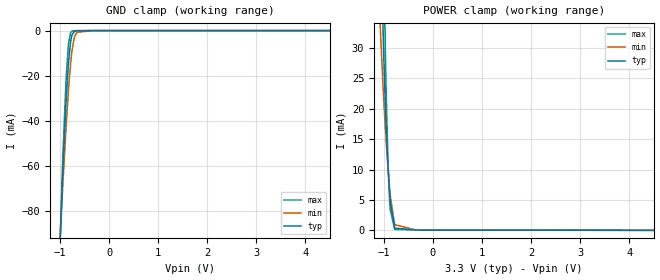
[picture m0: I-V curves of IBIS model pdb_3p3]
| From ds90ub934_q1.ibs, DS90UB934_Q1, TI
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|   pdb_3p3 Model
[Model]   pdb_3p3
Model_type   Input
Vinl = 0.8
Vinh = 2.0
|   typ   min   max
|   (nom PVT)   (fast PVT)   (slow PVT)
C_comp   3.681e-13   2.804e-13   4.593e-13
| Where nom  PVT is Nominal Process, 3.3V, 27C
|   Fast PVT is Strong Process,  3.6V, -40C
|   Slow PVT is Weak Process,   3V, 125C
[Voltage Range]   3.3   3   3.6
|Junction Temperature
[Temperature Range]   27   125   -40
[Power Clamp Reference]   3.3   3   3.6
[GND Clamp Reference]   0   0   0
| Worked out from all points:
|   GND clamp passes 1 mA (typ) near -0.73 V on its own axis
|   POWER clamp passes 1 mA (typ) near -0.79 V on its own axis
[GND Clamp]
|   Voltage   I(typ)   I(min)   I(max)
-3.3V     -1.797A    -1.612A    -1.945A
-1.064V   -133.6mA   -125.7mA   -138.3mA
-1.006V   -97.21mA   -96.37mA   -97.14mA
-943.8mV  -61.67mA   -68.3mA    -56.21mA
-879mV    -31.66mA   -43.11mA   -21.94mA
-828mV    -14.09mA   -26.09mA   -5.559mA
-785.4mV  -4.87mA    -14.55mA   -910.5uA
-758.4mV  -1.986mA   -8.99mA    -260uA
-706.2mV  -276.2uA   -2.713mA   -41.23uA
-660mV    -56.83uA   -778.2uA   -23.84uA
-330mV    -10.79uA   -9.203uA   -13.02uA
6.6V      0A         0A         0A
[POWER Clamp]
|   Voltage   I(typ)   I(min)   I(max)
-3.3V     1.763A     1.504A     1.972A
-1.073V   55.6mA     33.35mA    89.82mA
-1.016V   33.03mA    23.62mA    53.7mA
-1.003V   28.93mA    21.62mA    46.15mA
-960mV    18.29mA    15.63mA    25.27mA
-957mV    17.68mA    15.24mA    24.08mA
-916.8mV  10.65mA    10.4mA     11.45mA
-881.1mV  5.938mA    6.743mA    4.812mA
-870mV    4.762mA    5.756mA    3.458mA
-778.8mV  382.2uA    949.9uA    176.4uA
-330mV    72.53uA    57.25uA    93.64uA
6.6V      0A         0A         0A
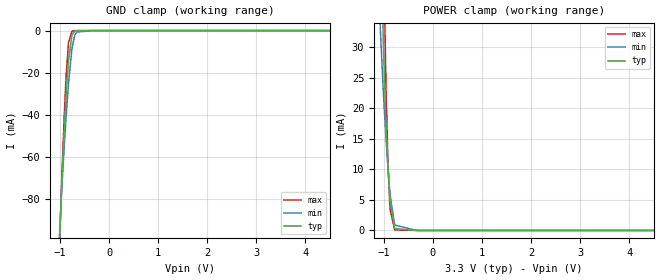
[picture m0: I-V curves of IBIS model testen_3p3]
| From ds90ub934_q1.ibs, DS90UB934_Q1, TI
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|   testen_3p3 Model
[Model]   testen_3p3
Model_type   Input
Vinl = 0.8
Vinh = 2.0
|   typ   min   max
|   (nom PVT)   (fast PVT)   (slow PVT)
C_comp   3.055e-13   2.043e-13   4.168e-13
| Where nom  PVT is Nominal Process, 3.3V, 27C
|   Fast PVT is Strong Process,  3.6V, -40C
|   Slow PVT is Weak Process,   3V, 125C
[Voltage Range]   3.3   3   3.6
|Junction Temperature
[Temperature Range]   27   125   -40
[Power Clamp Reference]   3.3   3   3.6
[GND Clamp Reference]   0   0   0
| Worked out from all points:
|   GND clamp passes 1 mA (typ) near -0.73 V on its own axis
|   POWER clamp passes 1 mA (typ) near -0.79 V on its own axis
[GND Clamp]
|   Voltage   I(typ)   I(min)   I(max)
-3.3V     -1.759A    -1.583A    -1.903A
-1.077V   -139.9mA   -129.1mA   -147.7mA
-1.046V   -120.4mA   -113.2mA   -125.7mA
-960.3mV  -69.8mA    -73.13mA   -67.15mA
-912mV    -45.67mA   -53.72mA   -38.51mA
-876mV    -30.4mA    -40.59mA   -21.01mA
-828mV    -14.16mA   -25.05mA   -5.707mA
-758.4mV  -2.04mA    -8.454mA   -275.7uA
-702.9mV  -257uA     -2.263mA   -28.48uA
-660mV    -52.91uA   -694.8uA   -11.39uA
-330mV    -1.485uA   -1.51uA    -1.725uA
6.6V      0A         0A         0A
[POWER Clamp]
|   Voltage   I(typ)   I(min)   I(max)
-3.3V     1.763A     1.504A     1.971A
-1.073V   55.52mA    33.28mA    89.72mA
-1.016V   32.94mA    23.55mA    53.59mA
-1.003V   28.85mA    21.56mA    46.04mA
-960mV    18.21mA    15.56mA    25.17mA
-957mV    17.6mA     15.17mA    23.97mA
-916.8mV  10.57mA    10.33mA    11.34mA
-881.1mV  5.858mA    6.679mA    4.711mA
-870mV    4.683mA    5.693mA    3.357mA
-778.8mV  304.8uA    888uA      77.36uA
-330mV    3.603uA    2.755uA    4.801uA
6.6V      0A         0A         0A
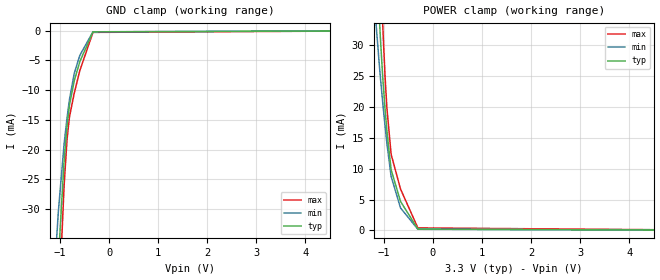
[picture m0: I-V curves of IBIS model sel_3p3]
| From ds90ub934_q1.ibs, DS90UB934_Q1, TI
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|   sel_3p3 Model
[Model]   sel_3p3
Model_type   Input
Vinl = 0.8
Vinh = 2
|   typ   min   max
|   (nom PVT)   (fast PVT)   (slow PVT)
C_comp   3.725e-13   3.725e-13   4.390e-13
| Where nom  PVT is Nominal Process, 3.3V, 27C
|   Fast PVT is Strong Process,  3.6V, -40C
|   Slow PVT is Weak Process,   3V, 125C
[Voltage Range]   3.3   3   3.6
[Temperature Range]   27   125   -40
[Power Clamp Reference]   3.3   3   3.6
[GND Clamp Reference]   0   0   0
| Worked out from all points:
|   GND clamp passes 1 mA (typ) near -0.38 V on its own axis
[GND Clamp]
|   Voltage   I(typ)   I(min)   I(max)
-3.3V     -491.8mA   -423.9mA   -559.8mA
-1.239V   -75.42mA   -59.14mA   -91.74mA
-1.131V   -55.26mA   -42.87mA   -68mA
-1.118V   -52.97mA   -41.09mA   -65.28mA
-1.035V   -38.5mA    -30.32mA   -47.74mA
-916.8mV  -21.68mA   -18.91mA   -25.82mA
-858mV    -16mA      -14.63mA   -18.24mA
-808.8mV  -12.51mA   -11.55mA   -14.49mA
-711mV    -8.408mA   -7.157mA   -10.49mA
-597mV    -5.192mA   -4.143mA   -6.684mA
-330mV    -214.7uA   -206.2uA   -301.9uA
6.6V      0A         0A         0A
[POWER Clamp]
|   Voltage   I(typ)   I(min)   I(max)
-3.3V     582.6mA    466.2mA    697.7mA
-1.155V   45.95mA    33.09mA    64.94mA
-1.089V   34.1mA     26.5mA     48.29mA
-1.072V   31.39mA    24.92mA    44.15mA
-1.023V   24.87mA    20.74mA    33.49mA
-1.014V   23.81mA    19.99mA    31.71mA
-975mV    19.64mA    16.89mA    24.89mA
-937.2mV  16.08mA    14.07mA    19.74mA
-852mV    9.838mA    8.767mA    12.34mA
-660mV    4.699mA    3.648mA    6.709mA
-306.9mV  228.3uA    198.8uA    415.9uA
6.6V      0A         0A         0A
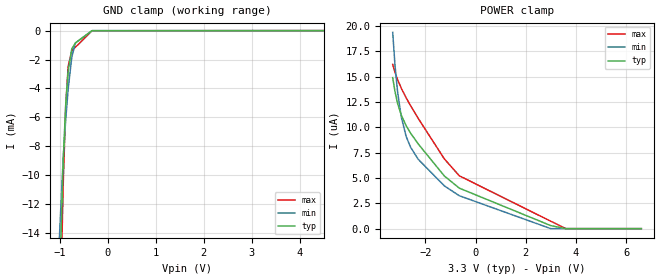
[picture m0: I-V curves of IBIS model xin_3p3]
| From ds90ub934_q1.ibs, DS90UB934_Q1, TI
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|   xin_3p3 Model
[Model]   xin_3p3
Model_type   Input
Vinl = 0.8
Vinh = 2
|   typ   min   max
|   (nom PVT)   (fast PVT)   (slow PVT)
C_comp   1.620e-13   1.261e-13   2.014e-13
| Where nom  PVT is Nominal Process, 3.3V, 27C
|   Fast PVT is Strong Process,  3.6V, -40C
|   Slow PVT is Weak Process,   3V, 125C
[Voltage Range]   3.3   3   3.6
|Junction Temperature
[Temperature Range]   27   125   -40
[Power Clamp Reference]   3.3   3   3.6
[GND Clamp Reference]   0   0   0
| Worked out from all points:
|   GND clamp passes 1 mA (typ) near -0.71 V on its own axis
[GND Clamp]
|   Voltage   I(typ)   I(min)   I(max)
-3.3V     -430mA     -361.4mA   -493.6mA
-1.134V   -36.71mA   -27.33mA   -45.03mA
-1.072V   -26.93mA   -20.21mA   -33.21mA
-1.043V   -22.67mA   -17.3mA    -27.98mA
-1.007V   -17.67mA   -14.08mA   -21.78mA
-930.6mV  -9.002mA   -8.818mA   -10.62mA
-877.8mV  -5.092mA   -6.133mA   -5.214mA
-826.8mV  -2.792mA   -4.031mA   -2.458mA
-751.2mV  -1.26mA    -1.833mA   -1.393mA
-675mV    -852.5uA   -851uA     -1.149mA
-330mV    -7.435uA   -6.971uA   -11.19uA
6.6V      0A         0A         0A
[POWER Clamp]
|   Voltage   I(typ)   I(min)   I(max)
-3.3V     14.9uA     19.36uA    16.2uA
-3.21V    13.53uA    16.15uA    15.43uA
-3.106V   12.36uA    13.49uA    14.7uA
-2.958V   11.2uA     11.01uA    13.85uA
-2.766V   10.16uA    9.105uA    12.91uA
-2.591V   9.43uA     8.045uA    12.14uA
-2.277V   8.336uA    6.822uA    10.85uA
-1.244V   5.196uA    4.223uA    6.88uA
-646.8mV  3.995uA    3.246uA    5.211uA
2.997V    297.9nA    0A         732.8nA
3.594V    0A         0A         0A
6.6V      0A         0A         0A
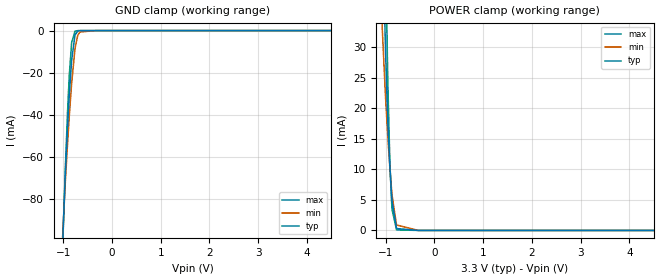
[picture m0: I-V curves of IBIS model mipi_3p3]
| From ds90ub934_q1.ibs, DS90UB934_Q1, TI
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|   mipi_3p3 Model
[Model]   mipi_3p3
Model_type   Input
Vinl = 0.8
Vinh = 2
|   typ   min   max
|   (nom PVT)   (fast PVT)   (slow PVT)
C_comp   3.055e-13   2.043e-13   4.178e-13
| Where nom  PVT is Nominal Process, 3.3V, 27C
|   Fast PVT is Strong Process,  3.6V, -40C
|   Slow PVT is Weak Process,   3V, 125C
[Voltage Range]   3.3   3   3.6
|Junction Temperature
[Temperature Range]   27   125   -40
[Power Clamp Reference]   3.3   3   3.6
[GND Clamp Reference]   0   0   0
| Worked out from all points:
|   GND clamp passes 1 mA (typ) near -0.73 V on its own axis
|   POWER clamp passes 1 mA (typ) near -0.79 V on its own axis
[GND Clamp]
|   Voltage   I(typ)   I(min)   I(max)
-3.3V     -1.759A    -1.583A    -1.903A
-1.077V   -139.9mA   -129.1mA   -147.7mA
-1.046V   -120.4mA   -113.2mA   -125.7mA
-960.3mV  -69.79mA   -73.12mA   -67.13mA
-912mV    -45.66mA   -53.71mA   -38.49mA
-876mV    -30.39mA   -40.58mA   -21mA
-828mV    -14.15mA   -25.04mA   -5.695mA
-758.4mV  -2.032mA   -8.447mA   -265.5uA
-702.9mV  -249.6uA   -2.256mA   -19.47uA
-660mV    -46.28uA   -689.1uA   -3.329uA
-330mV    -336.9nA   -350.4nA   -407.3nA
6.6V      0A         0A         0A
[POWER Clamp]
|   Voltage   I(typ)   I(min)   I(max)
-3.3V     1.763A     1.504A     1.972A
-1.073V   55.54mA    33.29mA    89.74mA
-1.016V   32.96mA    23.57mA    53.61mA
-1.003V   28.87mA    21.57mA    46.06mA
-960mV    18.22mA    15.57mA    25.18mA
-957mV    17.61mA    15.19mA    23.99mA
-916.8mV  10.59mA    10.35mA    11.36mA
-881.1mV  5.872mA    6.691mA    4.728mA
-870mV    4.697mA    5.705mA    3.373mA
-778.8mV  316.4uA    897.9uA    91.82uA
-330mV    6.563uA    5.362uA    8.631uA
6.6V      0A         0A         0A
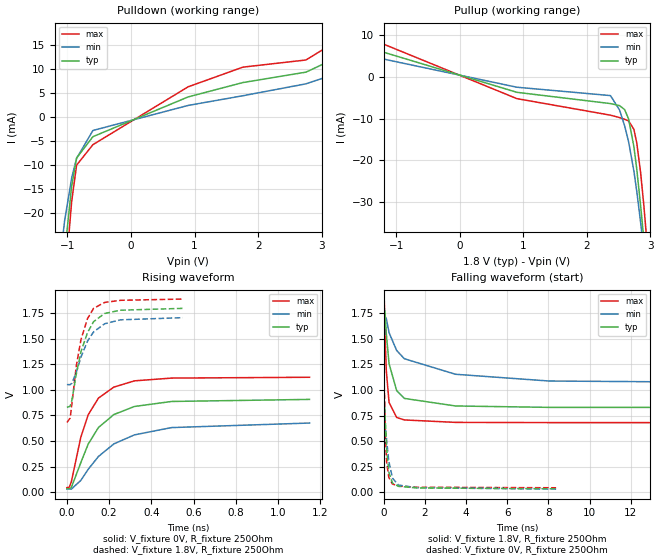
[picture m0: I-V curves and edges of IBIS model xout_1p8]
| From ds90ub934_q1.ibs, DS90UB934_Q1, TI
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|   xout_1p8 Model
[Model]   xout_1p8
Model_type   Output
Polarity   Inverting
Vmeas = 0.9
Vref = 0
Cref = 2pF
Rref = 400
|   typ   min   max
|   (nom PVT)   (fast PVT)   (slow PVT)
C_comp   3.237e-13   3.075e-13   3.282e-13
| Where nom  PVT is Nominal Process, 1.8V, 27C
|   Fast PVT is Strong Process,  1.89V, -40C
|   Slow PVT is Weak Process,   1.71V, 125C
[Voltage Range]   1.8   1.71   1.89
|Junction Temperature
[Temperature Range]   27   125   -40
[Pullup Reference]   1.8   1.71   1.89
[Pulldown Reference]   0   0   0
[Power Clamp Reference]   1.8   1.71   1.89
[GND Clamp Reference]   0   0   0
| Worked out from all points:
|   slope of the pulldown table from 0 to 0.27 V, typ, clamps not added: 169 ohm
|   slope of the pullup table from 0 to 0.27 V, typ, clamps not added: 222 ohm
|   falling waveform, V_fixture 1.8V, R_fixture 250Ohm: 20-80 % time 458ps typ, 2.41ns min, 175ps max; typ from 1.8 V to 0.828 V
|   rising waveform, V_fixture 0V, R_fixture 250Ohm: 20-80 % time 149ps typ, 218ps min, 107ps max; typ from 0.034 V to 0.906 V
|   rising waveform, V_fixture 1.8V, R_fixture 250Ohm: 20-80 % time 73.6ps typ, 83.7ps min, 62.1ps max; typ from 0.828 V to 1.8 V
|   falling waveform, V_fixture 0V, R_fixture 250Ohm: 20-80 % time 165ps typ, 265ps min, 113ps max; typ from 0.91 V to 0.034 V
[Pulldown]
|   Voltage   I(typ)   I(min)   I(max)
-1.8V     -162.8mA   -133.4mA   -187.7mA
-1.21V    -55.41mA   -41.88mA   -66.96mA
-1.146V   -44.56mA   -33.31mA   -54.29mA
-1.112V   -39.05mA   -29.13mA   -47.79mA
-1.044V   -28.43mA   -21.55mA   -35.11mA
-934.7mV  -14.46mA   -12.78mA   -17.7mA
-856.8mV  -8.583mA   -8.654mA   -10.07mA
-599.6mV  -4.133mA   -2.843mA   -5.796mA
898.4mV   4.142mA    2.37mA     6.249mA
1.761V    7.14mA     4.392mA    10.35mA
2.753V    9.305mA    6.871mA    11.84mA
3.6V      14.56mA    10.6mA     18.71mA
[Pullup]
|   Voltage   I(typ)   I(min)   I(max)
-1.8V     8.725mA    6.251mA    11.66mA
898.4mV   -3.677mA   -2.454mA   -5.198mA
2.371V    -6.387mA   -4.465mA   -9.173mA
2.514V    -6.876mA   -7.943mA   -9.755mA
2.595V    -7.838mA   -11.78mA   -10.17mA
2.657V    -10.15mA   -15.61mA   -10.56mA
2.74V     -16.77mA   -22.66mA   -12.6mA
2.785V    -22.19mA   -27.51mA   -15.86mA
2.846V    -31mA      -35.03mA   -23.07mA
2.897V    -39.16mA   -41.89mA   -31.01mA
2.957V    -49.38mA   -50.47mA   -41.83mA
3.6V      -168.8mA   -151.8mA   -176.6mA
[Ramp]
R_load = 250
|   typ   min   max
dV/dt_r   0.526075/1.51331e-10   0.391085/2.25282e-10   0.649945/1.08163e-10
dV/dt_f   0.582641/4.56977e-10   0.395262/2.42675e-09   0.725076/1.74409e-10
[Falling Waveform]
V_fixture = 1.8V
V_fixture_min = 1.71V
V_fixture_max = 1.89V
R_fixture = 250Ohm
|   Time   V(typ)   V(min)   V(max)
0s        1.8V       1.71V      1.89V
35.45ps   1.806V     1.714V     1.871V
81.15ps   1.739V     1.713V     1.484V
133.9ps   1.548V     1.699V     1.188V
266.9ps   1.257V     1.561V     878.3mV
636.2ps   994mV      1.387V     731.3mV
1.009ns   917.8mV    1.306V     707.2mV
3.494ns   843.8mV    1.154V     683.2mV
8.033ns   830.2mV    1.088V     681.1mV
34.51ns   828.3mV    1.051V     680.8mV
[Rising Waveform]
V_fixture = 0V
V_fixture_min = 0V
V_fixture_max = 0V
R_fixture = 250Ohm
|   Time   V(typ)   V(min)   V(max)
0s        33.55mV    29.25mV    43.31mV
11.54ps   32.41mV    28.39mV    48.28mV
20.98ps   44.89mV    29.02mV    100.7mV
66.01ps   288.3mV    114.2mV    537.8mV
101.1ps   470.3mV    223.5mV    757.2mV
149.4ps   631.8mV    348.3mV    919.4mV
222.3ps   758.4mV    471.2mV    1.027V
320ps     837.4mV    559.6mV    1.088V
495.8ps   886.3mV    630.8mV    1.115V
1.149ns   906.5mV    675.3mV    1.123V
[Rising Waveform]
V_fixture = 1.8V
V_fixture_min = 1.71V
V_fixture_max = 1.89V
R_fixture = 250Ohm
|   Time   V(typ)   V(min)   V(max)
0s        828.2mV    1.051V     680.8mV
15.39ps   839.2mV    1.051V     724mV
23.38ps   895.9mV    1.064V     858.1mV
44.34ps   1.152V     1.17V      1.231V
66.64ps   1.374V     1.321V     1.492V
97.42ps   1.559V     1.476V     1.696V
126.4ps   1.667V     1.567V     1.797V
178.5ps   1.747V     1.646V     1.855V
254.3ps   1.779V     1.685V     1.876V
549.1ps   1.797V     1.706V     1.888V
[Falling Waveform]
V_fixture = 0V
V_fixture_min = 0V
V_fixture_max = 0V
R_fixture = 250Ohm
|   Time   V(typ)   V(min)   V(max)
0s        910.3mV    681.1mV    1.127V
29.55ps   905.6mV    681.8mV    1.085V
51.2ps    858mV      670.7mV    907.1mV
97.42ps   652.5mV    614mV      516mV
149.4ps   424.2mV    508.4mV    294.1mV
254.3ps   196.6mV    305mV      145.4mV
433.5ps   89.03mV    137mV      79.75mV
726.6ps   57.1mV     69.44mV    60.39mV
1.619ns   41.92mV    43.67mV    48.52mV
8.374ns   33.7mV     29.72mV    43.37mV
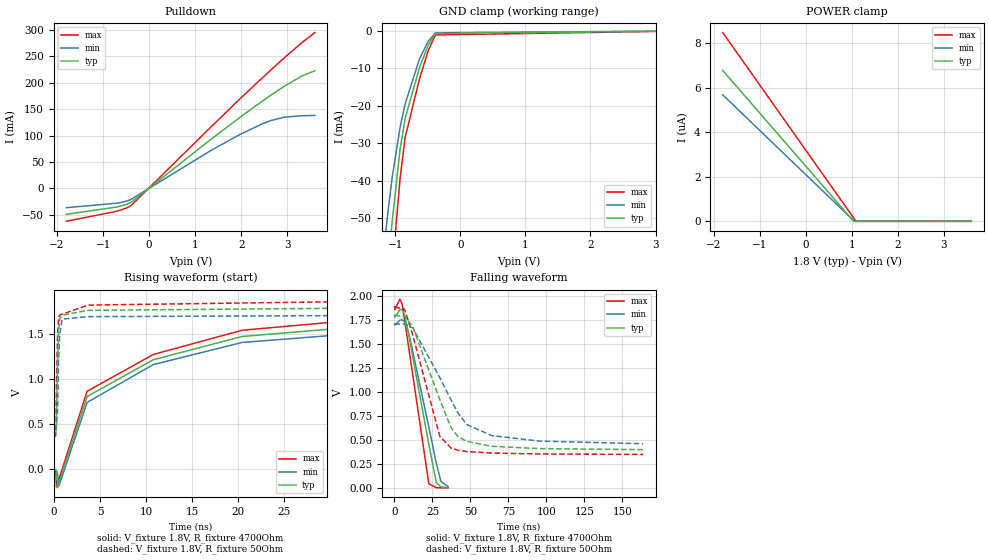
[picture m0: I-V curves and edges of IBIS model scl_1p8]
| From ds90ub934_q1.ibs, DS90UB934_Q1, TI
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|   scl_1p8 Model
[Model]   scl_1p8
Model_type   I/O_open_drain
Polarity   Non-Inverting
Vinl = 0.63
Vinh = 1.17
Vmeas = 0.9
Vref = 1.8
Cref = 550pF
Rref = 4700
|   typ   min   max
|   (nom PVT)   (fast PVT)   (slow PVT)
C_comp   1.679e-13   1.203e-13   2.326e-13
| Where nom  PVT is Nominal Process, 1.8V, 27C
|   Fast PVT is Strong Process,  1.89V, -40C
|   Slow PVT is Weak Process,   1.71V, 125C
[Voltage Range]   1.8   1.71   1.89
|Junction Temperature
[Temperature Range]   27   125   -40
[Pullup Reference]   1.8   1.71   1.89
[Pulldown Reference]   0   0   0
[Power Clamp Reference]   1.8   1.71   1.89
[GND Clamp Reference]   0   0   0
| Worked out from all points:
|   slope of the pulldown table from 0 to 0.27 V, typ, clamps not added: 14.3 ohm
|   GND clamp passes 1 mA (typ) near -0.39 V on its own axis
|   falling waveform, V_fixture 1.8V, R_fixture 4700Ohm: 20-80 % time 12.4ns typ, 13.4ns min, 10.4ns max; typ from 1.8 V to 0.009 V
|   rising waveform, V_fixture 1.8V, R_fixture 4700Ohm: 20-80 % time 16.2ns typ, 15.7ns min, 16.5ns max; typ from 0.005 V to 1.77 V
|   falling waveform, V_fixture 1.8V, R_fixture 50Ohm: 20-80 % time 19.5ns typ, 24.7ns min, 15.2ns max; typ from 1.8 V to 0.403 V
|   rising waveform, V_fixture 1.8V, R_fixture 50Ohm: 20-80 % time 202ps typ, 219ps min, 193ps max; typ from 0.4 V to 1.8 V
[Pulldown]
|   Voltage   I(typ)   I(min)   I(max)
-1.8V     -49.44mA   -36.8mA    -62.61mA
-695.3mV  -35.34mA   -28.28mA   -43.37mA
-486mV    -30.43mA   -24.34mA   -37.28mA
-387.5mV  -26.3mA    -20.85mA   -32.43mA
1.33V     91.9mA     71.05mA    115.1mA
1.976V    134.7mA    102.2mA    169.7mA
2.448V    164.5mA    121.8mA    208.5mA
2.632V    175.8mA    128.1mA    223.4mA
2.932V    193.2mA    134.8mA    247mA
3.322V    213.1mA    137.5mA    276.4mA
3.6V      222.8mA    138.1mA    295.2mA
[GND Clamp]
|   Voltage   I(typ)   I(min)   I(max)
-1.8V     -207.4mA   -175.8mA   -243.8mA
-1.265V   -94.36mA   -74.19mA   -114.7mA
-1.174V   -75.65mA   -58.47mA   -93.16mA
-1.147V   -70.31mA   -54.11mA   -86.94mA
-1.105V   -62.18mA   -47.64mA   -77.42mA
-1.042V   -50.45mA   -38.76mA   -63.41mA
-923.4mV  -31.63mA   -25.78mA   -39.42mA
-845.6mV  -23.32mA   -19.48mA   -28.43mA
-624.4mV  -9.782mA   -7.458mA   -12.75mA
-490.1mV  -3.78mA    -2.744mA   -5.24mA
-379.8mV  -706.7uA   -541.1uA   -1.103mA
3.6V      0A         0A         0A
[POWER Clamp]
|   Voltage   I(typ)   I(min)   I(max)
-1.8V     6.775uA    5.679uA    8.476uA
1.044V    0A         30.57nA    149.8nA
1.094V    0A         0A         0A
3.6V      0A         0A         0A
[Ramp]
R_load = 4700
|   typ   min   max
dV/dt_r   1.06113/1.59247e-08   1.00749/1.54421e-08   1.11424/1.62279e-08
dV/dt_f   1.06965/1.23656e-08   1.01589/1.34086e-08   1.12225/1.03076e-08
[Falling Waveform]
V_fixture = 1.8V
V_fixture_min = 1.71V
V_fixture_max = 1.89V
R_fixture = 4700Ohm
|   Time   V(typ)   V(min)   V(max)
0s        1.8V       1.71V      1.89V
196.9ps   1.782V     1.7V       1.861V
3.587ns   1.861V     1.75V      1.97V
5.027ns   1.863V     1.755V     1.917V
6.828ns   1.795V     1.735V     1.737V
9.502ns   1.586V     1.61V      1.451V
22.61ns   456.5mV    637.9mV    48mV
27.5ns    60.48mV    264.7mV    7.488mV
30.53ns   14.86mV    72.8mV     6.297mV
35.29ns   9mV        18.58mV    5.547mV
[Rising Waveform]
V_fixture = 1.8V
V_fixture_min = 1.71V
V_fixture_max = 1.89V
R_fixture = 4700Ohm
|   Time   V(typ)   V(min)   V(max)
0s        5.452mV    6.55mV     4.611mV
217.5ps   -10mV      -7.254mV   -19.34mV
283ps     -27.08mV   -12.26mV   -195mV
414.1ps   -206mV     -57.66mV   -174.8mV
570.3ps   -144.4mV   -179.4mV   -105.4mV
3.61ns    805.9mV    740.3mV    863.9mV
10.78ns   1.213V     1.159V     1.271V
20.4ns    1.47V      1.404V     1.539V
47.64ns   1.703V     1.621V     1.788V
100ns     1.774V     1.686V     1.862V
[Falling Waveform]
V_fixture = 1.8V
V_fixture_min = 1.71V
V_fixture_max = 1.89V
R_fixture = 50Ohm
|   Time   V(typ)   V(min)   V(max)
0s        1.8V       1.71V      1.89V
6.663ns   1.796V     1.71V      1.865V
12.01ns   1.682V     1.67V      1.597V
29.82ns   923.7mV    1.154V     542mV
37.29ns   631.5mV    919.1mV    418.7mV
41.72ns   539.6mV    786.5mV    398mV
47.54ns   490mV      665.3mV    383.7mV
63.91ns   438.2mV    550mV      367.7mV
95.91ns   414mV      491.6mV    358.3mV
163.6ns   403.3mV    465.3mV    353.7mV
[Rising Waveform]
V_fixture = 1.8V
V_fixture_min = 1.71V
V_fixture_max = 1.89V
R_fixture = 50Ohm
|   Time   V(typ)   V(min)   V(max)
0s        400mV      456.5mV    352.4mV
201.7ps   404.9mV    452.5mV    372.7mV
243.4ps   425.5mV    458.6mV    504.9mV
271.6ps   455.6mV    468.3mV    851.8mV
396.9ps   1.177V     639.6mV    1.464V
510.2ps   1.502V     1.169V     1.681V
638.7ps   1.665V     1.483V     1.708V
902.1ps   1.705V     1.663V     1.717V
3.706ns   1.76V      1.69V      1.818V
51.57ns   1.8V       1.71V      1.884V
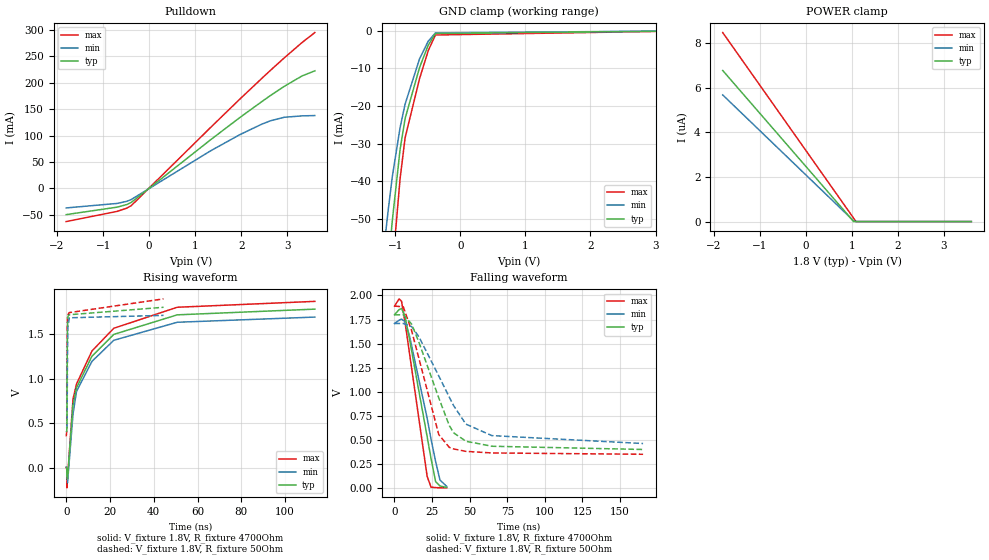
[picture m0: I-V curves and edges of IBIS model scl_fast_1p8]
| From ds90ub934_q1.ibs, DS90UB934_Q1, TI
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|   scl_fast_1p8 Model
[Model]   scl_fast_1p8
Model_type   I/O_open_drain
Polarity   Non-Inverting
Vinl = 0.63
Vinh = 1.17
Vmeas = 0.9
Vref = 1.8
Cref = 400pF
Rref = 4700
|   typ   min   max
|   (nom PVT)   (fast PVT)   (slow PVT)
C_comp   1.676e-13   1.206e-13   2.322e-13
| Where nom  PVT is Nominal Process, 1.8V, 27C
|   Fast PVT is Strong Process,  1.89V, -40C
|   Slow PVT is Weak Process,   1.71V, 125C
[Voltage Range]   1.8   1.71   1.89
|Junction Temperature
[Temperature Range]   27   125   -40
[Pullup Reference]   1.8   1.71   1.89
[Pulldown Reference]   0   0   0
[Power Clamp Reference]   1.8   1.71   1.89
[GND Clamp Reference]   0   0   0
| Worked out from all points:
|   slope of the pulldown table from 0 to 0.27 V, typ, clamps not added: 14.3 ohm
|   GND clamp passes 1 mA (typ) near -0.39 V on its own axis
|   falling waveform, V_fixture 1.8V, R_fixture 4700Ohm: 20-80 % time 12.4ns typ, 13.3ns min, 10.4ns max; typ from 1.8 V to 0.01 V
|   rising waveform, V_fixture 1.8V, R_fixture 4700Ohm: 20-80 % time 16.1ns typ, 15.5ns min, 16.4ns max; typ from 0.005 V to 1.78 V
|   falling waveform, V_fixture 1.8V, R_fixture 50Ohm: 20-80 % time 19.4ns typ, 24.7ns min, 15.1ns max; typ from 1.8 V to 0.403 V
|   rising waveform, V_fixture 1.8V, R_fixture 50Ohm: 20-80 % time 201ps typ, 222ps min, 189ps max; typ from 0.4 V to 1.8 V
[Pulldown]
|   Voltage   I(typ)   I(min)   I(max)
-1.8V     -49.44mA   -36.8mA    -62.61mA
-695.3mV  -35.34mA   -28.28mA   -43.37mA
-486mV    -30.43mA   -24.34mA   -37.28mA
-387.5mV  -26.3mA    -20.85mA   -32.43mA
1.33V     91.9mA     71.05mA    115.1mA
1.976V    134.7mA    102.2mA    169.7mA
2.448V    164.5mA    121.8mA    208.5mA
2.632V    175.8mA    128.1mA    223.4mA
2.932V    193.2mA    134.8mA    247mA
3.322V    213.1mA    137.5mA    276.4mA
3.6V      222.8mA    138.1mA    295.2mA
[GND Clamp]
|   Voltage   I(typ)   I(min)   I(max)
-1.8V     -207.4mA   -175.8mA   -243.8mA
-1.265V   -94.36mA   -74.19mA   -114.7mA
-1.174V   -75.65mA   -58.47mA   -93.16mA
-1.147V   -70.31mA   -54.11mA   -86.94mA
-1.105V   -62.18mA   -47.64mA   -77.42mA
-1.042V   -50.45mA   -38.76mA   -63.41mA
-923.4mV  -31.63mA   -25.78mA   -39.42mA
-845.6mV  -23.32mA   -19.48mA   -28.43mA
-624.4mV  -9.782mA   -7.458mA   -12.75mA
-490.1mV  -3.78mA    -2.744mA   -5.24mA
-379.8mV  -706.7uA   -541.1uA   -1.103mA
3.6V      0A         0A         0A
[POWER Clamp]
|   Voltage   I(typ)   I(min)   I(max)
-1.8V     6.775uA    5.679uA    8.476uA
1.044V    0A         30.57nA    149.8nA
1.094V    0A         0A         0A
3.6V      0A         0A         0A
[Ramp]
R_load = 4700
|   typ   min   max
dV/dt_r   1.06794/1.63945e-08   1.01408/1.57236e-08   1.12077/1.66008e-08
dV/dt_f   1.06975/1.23603e-08   1.01613/1.33756e-08   1.1223/1.03164e-08
[Falling Waveform]
V_fixture = 1.8V
V_fixture_min = 1.71V
V_fixture_max = 1.89V
R_fixture = 4700Ohm
|   Time   V(typ)   V(min)   V(max)
0s        1.8V       1.71V      1.89V
3.084ns   1.854V     1.743V     1.965V
4.682ns   1.865V     1.755V     1.941V
6.929ns   1.79V      1.731V     1.731V
9.836ns   1.561V     1.591V     1.416V
21.73ns   534.2mV    727.2mV    124mV
24.3ns    311.2mV    509.6mV    12.77mV
27.34ns   69.95mV    279.7mV    7.889mV
30.23ns   25.07mV    86.47mV    6.387mV
34.72ns   9.677mV    20.95mV    5.48mV
[Rising Waveform]
V_fixture = 1.8V
V_fixture_min = 1.71V
V_fixture_max = 1.89V
R_fixture = 4700Ohm
|   Time   V(typ)   V(min)   V(max)
0s        5.452mV    6.55mV     4.611mV
236.5ps   -9.395mV   -2.227mV   -19.22mV
338.8ps   -89.94mV   -13.84mV   -224mV
581.4ps   -121.4mV   -166.9mV   -117.5mV
3.084ns   705.9mV    601.1mV    769.2mV
4.682ns   897.6mV    856.3mV    939.3mV
11.75ns   1.251V     1.193V     1.309V
21.73ns   1.495V     1.429V     1.564V
50.72ns   1.714V     1.631V     1.799V
113.6ns   1.778V     1.689V     1.865V
[Falling Waveform]
V_fixture = 1.8V
V_fixture_min = 1.71V
V_fixture_max = 1.89V
R_fixture = 50Ohm
|   Time   V(typ)   V(min)   V(max)
0s        1.8V       1.71V      1.89V
5.863ns   1.799V     1.71V      1.883V
11.39ns   1.704V     1.677V     1.635V
16.28ns   1.514V     1.571V     1.345V
29.45ns   937.9mV    1.166V     557.1mV
36.47ns   650.3mV    944.8mV    424.7mV
39.38ns   575.6mV    856.3mV    408.4mV
47.5ns    488.8mV    666.2mV    383.8mV
64.76ns   436.8mV    547.1mV    367.2mV
165.3ns   403.2mV    465.1mV    353.6mV
[Rising Waveform]
V_fixture = 1.8V
V_fixture_min = 1.71V
V_fixture_max = 1.89V
R_fixture = 50Ohm
|   Time   V(typ)   V(min)   V(max)
0s        400mV      456.5mV    352.4mV
247.2ps   412.5mV    452.4mV    416.8mV
300.9ps   466mV      464.9mV    986.5mV
343.8ps   695mV      486.2mV    1.202V
420.4ps   1.168V     587.9mV    1.483V
490.6ps   1.403V     955.8mV    1.637V
587.4ps   1.582V     1.31V      1.704V
775ps     1.698V     1.583V     1.716V
1.391ns   1.715V     1.681V     1.739V
44.47ns   1.799V     1.708V     1.893V
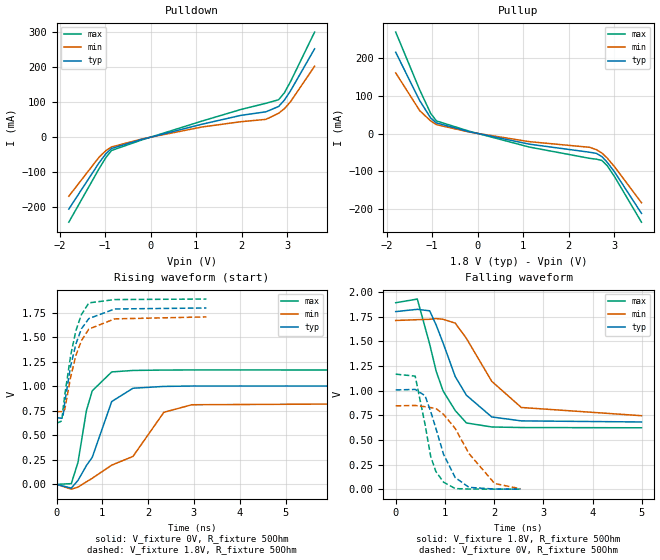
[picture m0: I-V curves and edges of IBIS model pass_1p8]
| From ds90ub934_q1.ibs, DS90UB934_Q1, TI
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|   pass_1p8 Model
[Model]   pass_1p8
Model_type   Output
Polarity   Non-Inverting
Vmeas = 0.9
Vref = 0
Cref = 2pF
Rref = 60
|   typ   min   max
|   (nom PVT)   (fast PVT)   (slow PVT)
C_comp   2.656e-13   2.335e-13   3.165e-13
| Where nom  PVT is Nominal Process, 1.8V, 27C
|   Fast PVT is Strong Process,  1.89V, -40C
|   Slow PVT is Weak Process,   1.71V, 125C
[Voltage Range]   1.8   1.71   1.89
|Junction Temperature
[Temperature Range]   27   125   -40
[Pullup Reference]   1.8   1.71   1.89
[Pulldown Reference]   0   0   0
[Power Clamp Reference]   1.8   1.71   1.89
[GND Clamp Reference]   0   0   0
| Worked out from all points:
|   slope of the pulldown table from 0 to 0.27 V, typ, clamps not added: 30.2 ohm
|   slope of the pullup table from 0 to 0.27 V, typ, clamps not added: 38.4 ohm
|   falling waveform, V_fixture 1.8V, R_fixture 50Ohm: 20-80 % time 625ps typ, 794ps min, 489ps max; typ from 1.8 V to 0.681 V
|   rising waveform, V_fixture 0V, R_fixture 50Ohm: 20-80 % time 494ps typ, 1.1ns min, 292ps max; typ from 0 V to 1 V
|   rising waveform, V_fixture 1.8V, R_fixture 50Ohm: 20-80 % time 333ps typ, 359ps min, 299ps max; typ from 0.681 V to 1.8 V
|   falling waveform, V_fixture 0V, R_fixture 50Ohm: 20-80 % time 397ps typ, 658ps min, 284ps max; typ from 1.01 V to 0.001 V
[Pulldown]
|   Voltage   I(typ)   I(min)   I(max)
-1.8V     -204.9mA   -168.2mA   -242.2mA
-1.14V    -74.05mA   -57.95mA   -91.01mA
-983.5mV  -47.02mA   -38.22mA   -57.84mA
-859.5mV  -32.21mA   -27.87mA   -37.96mA
-180mV    -5.931mA   -4.799mA   -7.301mA
1.122V    36.59mA    28.69mA    45.51mA
1.982V    61.94mA    43.89mA    78.72mA
2.531V    72.03mA    50.54mA    96.33mA
2.808V    87.1mA     67.76mA    106.3mA
2.936V    105.2mA    80.8mA     126.1mA
3.073V    132.2mA    101.1mA    158.4mA
3.6V      251.4mA    201.7mA    299mA
[Pullup]
|   Voltage   I(typ)   I(min)   I(max)
-1.8V     214.5mA    160.1mA    267.8mA
-1.271V   86.46mA    60.19mA    114.8mA
-1.031V   41.06mA    33.19mA    52.98mA
-904.1mV  27.85mA    23.32mA    33.15mA
-180mV    4.715mA    3.74mA     5.904mA
1.131V    -28.04mA   -21.47mA   -35.67mA
2.463V    -49.5mA    -36.48mA   -65.64mA
2.608V    -52.39mA   -42.64mA   -67.72mA
2.73V     -60.91mA   -51.48mA   -71.16mA
2.848V    -76.01mA   -64.88mA   -85.06mA
3.005V    -100.9mA   -87.34mA   -113.2mA
3.6V      -210.9mA   -182.9mA   -234.2mA
[Ramp]
R_load = 50
|   typ   min   max
dV/dt_r   0.601969/4.93896e-10   0.504255/1.09983e-09   0.698787/2.90879e-10
dV/dt_f   0.671535/6.25911e-10   0.580754/7.96964e-10   0.760629/4.88631e-10
[Falling Waveform]
V_fixture = 1.8V
V_fixture_min = 1.71V
V_fixture_max = 1.89V
R_fixture = 50Ohm
|   Time   V(typ)   V(min)   V(max)
0s        1.8V       1.71V      1.89V
439.3ps   1.823V     1.718V     1.927V
690.3ps   1.808V     1.722V     1.47V
823.5ps   1.662V     1.729V     1.194V
962.8ps   1.482V     1.722V     996mV
1.21ns    1.141V     1.683V     796.5mV
1.437ns   952.2mV    1.528V     671.4mV
1.952ns   732.1mV    1.093V     630.6mV
2.552ns   692.4mV    828.2mV    625mV
4.993ns   681.3mV    744.9mV    622.4mV
[Rising Waveform]
V_fixture = 0V
V_fixture_min = 0V
V_fixture_max = 0V
R_fixture = 50Ohm
|   Time   V(typ)   V(min)   V(max)
0s        1.128uV    5.699uV    491.1nV
322.5ps   -37.9mV    -48.84mV   7.597mV
468.9ps   40.54mV    -27.97mV   225.4mV
652.4ps   191.9mV    26.02mV    751.8mV
779.9ps   276.2mV    62.36mV    954.5mV
1.205ns   845.1mV    196.3mV    1.147V
1.669ns   980.6mV    285.3mV    1.162V
2.343ns   999.1mV    735mV      1.166V
2.951ns   1.003V     812.1mV    1.167V
15ns      1.003V     840.4mV    1.165V
[Rising Waveform]
V_fixture = 1.8V
V_fixture_min = 1.71V
V_fixture_max = 1.89V
R_fixture = 50Ohm
|   Time   V(typ)   V(min)   V(max)
0s        680.7mV    742mV      622.2mV
113.8ps   673.8mV    741.6mV    646.3mV
145.1ps   710.7mV    735.8mV    778.3mV
181.2ps   841.9mV    767mV      915.1mV
309.9ps   1.21V      1.099V     1.319V
423.4ps   1.433V     1.316V     1.569V
543.8ps   1.587V     1.466V     1.732V
705.8ps   1.691V     1.584V     1.851V
1.27ns    1.789V     1.688V     1.885V
3.272ns   1.799V     1.708V     1.89V
[Falling Waveform]
V_fixture = 0V
V_fixture_min = 0V
V_fixture_max = 0V
R_fixture = 50Ohm
|   Time   V(typ)   V(min)   V(max)
0s        1.006V     844.9mV    1.166V
396.2ps   1.011V     848.5mV    1.146V
596.4ps   948mV      835.8mV    656.2mV
712.6ps   785.6mV    827mV      329.1mV
816.5ps   616.2mV    818mV      179.2mV
973.4ps   352.4mV    758.5mV    70.86mV
1.21ns    117.5mV    614mV      6.3mV
1.49ns    18.41mV    360.3mV    1.496mV
2.011ns   1.45mV     57.46mV    541.6uV
2.537ns   537.1uV    4.159mV    304.5uV
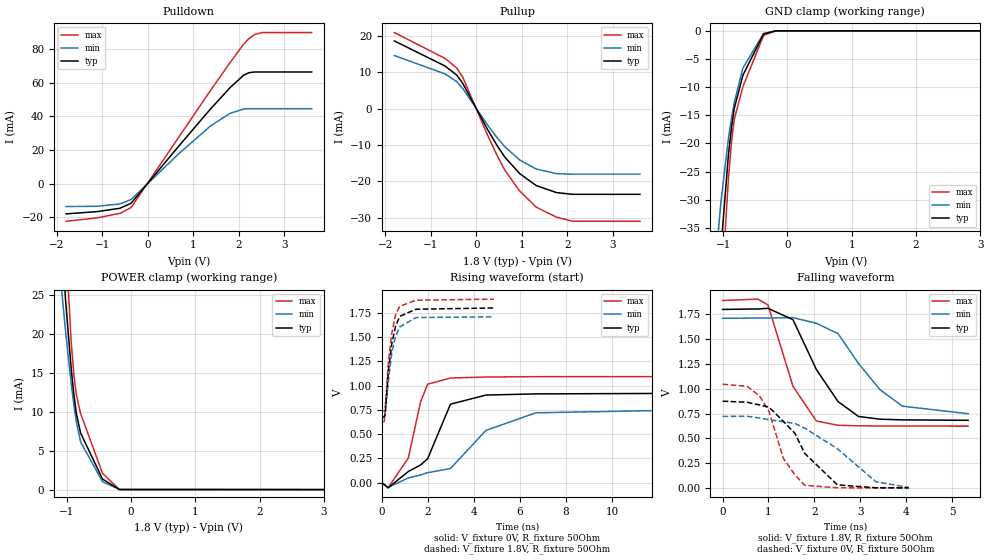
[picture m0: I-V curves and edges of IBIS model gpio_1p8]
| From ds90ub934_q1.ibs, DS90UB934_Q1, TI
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|   gpio_1p8 Model
[Model]   gpio_1p8
Model_type   I/O
Polarity   Non-Inverting
Enable   Active-Low
Vinl = 0.63
Vinh = 1.17
Vmeas = 0.9
Vref = 0
Cref = 2pF
Rref = 80
|   typ   min   max
|   (nom PVT)   (fast PVT)   (slow PVT)
C_comp   3.718e-13   3.701e-13   4.153e-13
| Where nom  PVT is Nominal Process, 1.8V, 27C
|   Fast PVT is Strong Process,  1.89V, -40C
|   Slow PVT is Weak Process,   1.71V, 125C
[Voltage Range]   1.8   1.71   1.89
|Junction Temperature
[Temperature Range]   27   125   -40
[Pullup Reference]   1.8   1.71   1.89
[Pulldown Reference]   0   0   0
[Power Clamp Reference]   1.8   1.71   1.89
[GND Clamp Reference]   0   0   0
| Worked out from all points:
|   slope of the pulldown table from 0 to 0.27 V, typ, clamps not added: 30.2 ohm
|   slope of the pullup table from 0 to 0.27 V, typ, clamps not added: 43.9 ohm
|   GND clamp passes 1 mA (typ) near -0.40 V on its own axis
|   falling waveform, V_fixture 1.8V, R_fixture 50Ohm: 20-80 % time 748ps typ, 967ps min, 555ps max; typ from 1.8 V to 0.682 V
|   rising waveform, V_fixture 0V, R_fixture 50Ohm: 20-80 % time 1.1ns typ, 1.78ns min, 675ps max; typ from 0 V to 0.874 V
|   rising waveform, V_fixture 1.8V, R_fixture 50Ohm: 20-80 % time 358ps typ, 369ps min, 331ps max; typ from 0.681 V to 1.8 V
|   falling waveform, V_fixture 0V, R_fixture 50Ohm: 20-80 % time 824ps typ, 1.21ns min, 503ps max; typ from 0.875 V to 0 V
[Pulldown]
|   Voltage   I(typ)   I(min)   I(max)
-1.8V     -18.1mA    -13.7mA    -22.52mA
-1.118V   -16.75mA   -13.57mA   -20.48mA
-616.7mV  -14.76mA   -12.18mA   -17.81mA
-370.8mV  -11.74mA   -9.537mA   -14.3mA
682.9mV   22.51mA    17.91mA    27.88mA
1.375V    44.46mA    34.38mA    55.51mA
1.806V    57.22mA    41.87mA    72.16mA
2.108V    64.69mA    44.51mA    83.23mA
2.222V    66.11mA    44.62mA    86.57mA
2.351V    66.54mA    44.62mA    88.92mA
2.507V    66.54mA    44.62mA    90.02mA
3.6V      66.54mA    44.62mA    90.04mA
[GND Clamp]
|   Voltage   I(typ)   I(min)   I(max)
-1.8V     -186.8mA   -154.6mA   -219.7mA
-1.184V   -65.39mA   -50.91mA   -80.03mA
-1.142V   -57.47mA   -44.58mA   -70.68mA
-1.093V   -48.73mA   -37.8mA    -60.24mA
-1.032V   -38.28mA   -30.14mA   -47.51mA
-918mV    -21.99mA   -19.11mA   -26.27mA
-867.6mV  -16.94mA   -15.37mA   -19.43mA
-826.6mV  -13.75mA   -12.69mA   -15.72mA
-692.5mV  -7.885mA   -6.615mA   -9.905mA
-371.2mV  -556.1uA   -459.4uA   -815.6uA
-180mV    -2.088uA   -5.52uA    -1.102uA
3.6V      0A         0A         0A
[Pullup]
|   Voltage   I(typ)   I(min)   I(max)
-1.8V     18.57mA    14.55mA    20.87mA
-687.6mV  11.7mA     9.532mA    13.79mA
-427.9mV  9.197mA    7.405mA    11.15mA
-295.6mV  6.918mA    5.493mA    8.587mA
252mV     -5.809mA   -4.572mA   -7.364mA
467.5mV   -10.33mA   -8.117mA   -13.11mA
628.7mV   -13.33mA   -10.48mA   -16.92mA
951.8mV   -17.82mA   -14.11mA   -22.6mA
1.319V    -21.16mA   -16.61mA   -27.08mA
1.761V    -23.08mA   -17.88mA   -29.82mA
2.117V    -23.57mA   -18.03mA   -30.96mA
3.6V      -23.57mA   -18.03mA   -30.98mA
[POWER Clamp]
|   Voltage   I(typ)   I(min)   I(max)
-1.8V     198.5mA    148.8mA    248.5mA
-1.154V   45.96mA    33.07mA    64.85mA
-1.133V   41.99mA    30.87mA    59.48mA
-1.076V   32.34mA    25.46mA    45.52mA
-1.018V   24.38mA    20.39mA    32.58mA
-930.6mV  15.62mA    13.69mA    19.01mA
-889mV    12.28mA    10.92mA    14.86mA
-849.6mV  9.776mA    8.708mA    12.16mA
-783.2mV  7.264mA    6.117mA    9.767mA
-443mV    1.357mA    1.021mA    2.096mA
-180mV    9.68uA     16.22uA    11.61uA
3.6V      0A         0A         0A
[Ramp]
R_load = 50
|   typ   min   max
dV/dt_r   0.524217/1.09833e-09   0.43397/1.76732e-09   0.626665/6.67214e-10
dV/dt_f   0.671532/7.48876e-10   0.581643/9.8061e-10   0.760362/5.53965e-10
[Falling Waveform]
V_fixture = 1.8V
V_fixture_min = 1.71V
V_fixture_max = 1.89V
R_fixture = 50Ohm
|   Time   V(typ)   V(min)   V(max)
0s        1.8V       1.71V      1.89V
766.7ps   1.805V     1.714V     1.904V
989ps     1.811V     1.713V     1.846V
1.533ns   1.697V     1.718V     1.025V
2.044ns   1.193V     1.66V      673.8mV
2.515ns   870.7mV    1.556V     631.5mV
2.96ns    720.5mV    1.255V     626.2mV
3.429ns   692.8mV    990.2mV    624.5mV
3.917ns   685.9mV    824.1mV    623.6mV
5.349ns   681.6mV    748.2mV    622.9mV
[Rising Waveform]
V_fixture = 0V
V_fixture_min = 0V
V_fixture_max = 0V
R_fixture = 50Ohm
|   Time   V(typ)   V(min)   V(max)
0s        1.128uV    5.641uV    494.5nV
262.6ps   -52.87mV   -47.73mV   -51.45mV
1.143ns   115.5mV    49.48mV    254.9mV
1.673ns   182.1mV    80.13mV    829.4mV
1.983ns   247.2mV    103.2mV    1.014V
2.976ns   808.6mV    146.4mV    1.078V
4.521ns   902.3mV    539.1mV    1.088V
6.688ns   914.5mV    719.5mV    1.092V
13.35ns   920.1mV    749mV      1.092V
300ns     873.7mV    723.3mV    1.044V
[Rising Waveform]
V_fixture = 1.8V
V_fixture_min = 1.71V
V_fixture_max = 1.89V
R_fixture = 50Ohm
|   Time   V(typ)   V(min)   V(max)
0s        680.7mV    740.6mV    622.7mV
100.4ps   673.9mV    740.5mV    631.3mV
133.3ps   701.5mV    734.3mV    750.6mV
158.8ps   785.6mV    747.9mV    860.5mV
282.6ps   1.165V     1.063V     1.257V
421ps     1.427V     1.332V     1.535V
586.7ps   1.609V     1.506V     1.727V
766.7ps   1.712V     1.603V     1.815V
1.469ns   1.786V     1.7V       1.879V
4.861ns   1.799V     1.708V     1.89V
[Falling Waveform]
V_fixture = 0V
V_fixture_min = 0V
V_fixture_max = 0V
R_fixture = 50Ohm
|   Time   V(typ)   V(min)   V(max)
0s        874.5mV    720.8mV    1.045V
532.1ps   863.9mV    722.2mV    1.025V
806ps     836.4mV    704.8mV    927.6mV
1.012ns   814.7mV    687.4mV    770.3mV
1.322ns   671.5mV    667.4mV    299.7mV
1.574ns   551.2mV    649.8mV    132.5mV
1.79ns    347.4mV    602.3mV    25.61mV
2.501ns   29.95mV    394.8mV    605.9uV
3.341ns   717uV      61.55mV    228.3uV
4.053ns   251.3uV    4.228mV    121.4uV
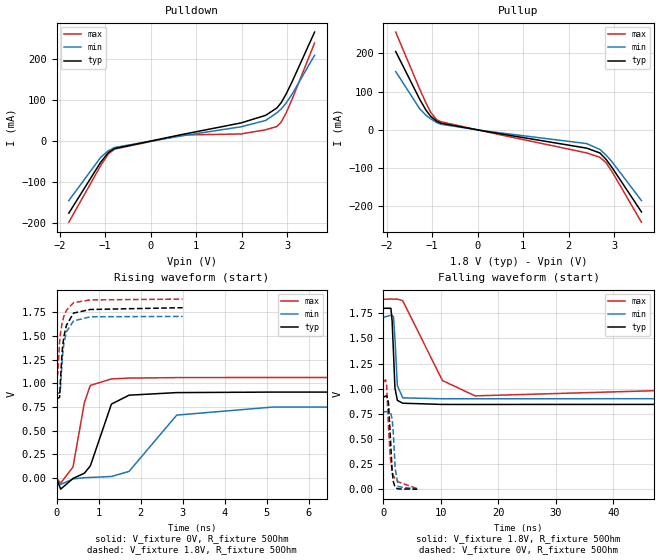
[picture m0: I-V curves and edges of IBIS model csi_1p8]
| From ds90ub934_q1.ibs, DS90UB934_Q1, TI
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|   csi_1p8 Model
[Model]   csi_1p8
Model_type   Output
Polarity   Non-Inverting
Vmeas = 0.9
Vref = 0
Cref = 2pF
Rref = 70
|   typ   min   max
|   (nom PVT)   (fast PVT)   (slow PVT)
C_comp   3.526e-13   3.319e-13   3.952e-13
| Where nom  PVT is Nominal Process, 1.8V, 27C
|   Fast PVT is Strong Process,  1.89V, -40C
|   Slow PVT is Weak Process,   1.71V, 125C
[Voltage Range]   1.8   1.71   1.89
|Junction Temperature
[Temperature Range]   27   125   -40
[Pullup Reference]   1.8   1.71   1.89
[Pulldown Reference]   0   0   0
[Power Clamp Reference]   1.8   1.71   1.89
[GND Clamp Reference]   0   0   0
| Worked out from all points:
|   slope of the pulldown table from 0 to 0.27 V, typ, clamps not added: 43.9 ohm
|   slope of the pullup table from 0 to 0.27 V, typ, clamps not added: 47.4 ohm
|   falling waveform, V_fixture 1.8V, R_fixture 50Ohm: 20-80 % time 400ps typ, 407ps min, 3.51ns max; typ from 1.8 V to 0.845 V
|   rising waveform, V_fixture 0V, R_fixture 50Ohm: 20-80 % time 383ps typ, 716ps min, 239ps max; typ from 0 V to 0.912 V
|   rising waveform, V_fixture 1.8V, R_fixture 50Ohm: 20-80 % time 138ps typ, 128ps min, 143ps max; typ from 0.845 V to 1.8 V
|   falling waveform, V_fixture 0V, R_fixture 50Ohm: 20-80 % time 490ps typ, 490ps min, 672ps max; typ from 0.915 V to 0 V
[Pulldown]
|   Voltage   I(typ)   I(min)   I(max)
-1.8V     -176.8mA   -146.1mA   -198.9mA
-1.104V   -52.87mA   -40.87mA   -61.16mA
-931.3mV  -28.6mA    -23.97mA   -31.69mA
-792.6mV  -18.67mA   -16.06mA   -19.98mA
682.9mV   15.51mA    12.34mA    14.4mA
1.982V    43.93mA    34.44mA    16.92mA
2.525V    62.52mA    49.96mA    27.23mA
2.772V    80.63mA    68.76mA    35.26mA
2.867V    93.65mA    78.27mA    46.23mA
2.969V    113.4mA    91.71mA    67.07mA
3.108V    145.3mA    114.7mA    102.3mA
3.6V      266.2mA    209.6mA    239.5mA
[Pullup]
|   Voltage   I(typ)   I(min)   I(max)
-1.8V     204.8mA    152.5mA    255.5mA
-1.271V   79.65mA    54.95mA    106.1mA
-1.134V   51.5mA     38.07mA    70mA
-1.031V   35.56mA    29mA       45.92mA
-904.1mV  23.05mA    19.68mA    26.97mA
-806.5mV  17.55mA    14.78mA    21.27mA
190.4mV   -4.062mA   -3.26mA    -5.041mA
2.396V    -47.64mA   -35.78mA   -60.1mA
2.687V    -60.32mA   -51.06mA   -71.63mA
2.822V    -77.04mA   -65.66mA   -85.52mA
2.963V    -100mA     -84.9mA    -110.9mA
3.6V      -214.3mA   -184.6mA   -241.1mA
[Ramp]
R_load = 50
|   typ   min   max
dV/dt_r   0.546977/3.82315e-10   0.458145/7.09336e-10   0.637849/2.3929e-10
dV/dt_f   0.573175/4.00235e-10   0.485129/4.05622e-10   0.493565/3.50843e-09
[Falling Waveform]
V_fixture = 1.8V
V_fixture_min = 1.71V
V_fixture_max = 1.89V
R_fixture = 50Ohm
|   Time   V(typ)   V(min)   V(max)
0s        1.8V       1.71V      1.89V
1.306ns   1.8V       1.731V     1.892V
1.515ns   1.676V     1.73V      1.892V
1.757ns   1.357V     1.716V     1.891V
2.007ns   1.008V     1.502V     1.891V
2.429ns   883.9mV    1.03V      1.891V
3.36ns    855.4mV    909mV      1.876V
10.27ns   843.3mV    899.5mV    1.081V
15.95ns   843.1mV    899.7mV    928.6mV
100ns     844.7mV    901.5mV    1.067V
[Rising Waveform]
V_fixture = 0V
V_fixture_min = 0V
V_fixture_max = 0V
R_fixture = 50Ohm
|   Time   V(typ)   V(min)   V(max)
0s        12.44uV    44.37uV    749.9uV
97.82ps   -116.7mV   -66.91mV   -53.43mV
392.3ps   -3.381mV   -8.627mV   117.7mV
663.4ps   51.77mV    4.336mV    797.8mV
804.3ps   128.4mV    6.98mV     978.8mV
1.306ns   780.8mV    17.03mV    1.047V
1.726ns   875.4mV    70.83mV    1.056V
2.861ns   902.6mV    665.2mV    1.061V
5.13ns    908mV      749.4mV    1.062V
100ns     911.6mV    763.6mV    1.064V
[Rising Waveform]
V_fixture = 1.8V
V_fixture_min = 1.71V
V_fixture_max = 1.89V
R_fixture = 50Ohm
|   Time   V(typ)   V(min)   V(max)
0s        845mV      902.1mV    1.074V
27.31ps   841.2mV    901.6mV    1.087V
73.03ps   852.5mV    894.6mV    1.432V
94.18ps   1.041V     951.9mV    1.529V
139.7ps   1.366V     1.275V     1.653V
175.5ps   1.495V     1.422V     1.709V
235.4ps   1.613V     1.544V     1.772V
404.7ps   1.742V     1.659V     1.852V
804.3ps   1.78V      1.703V     1.881V
3.002ns   1.799V     1.707V     1.89V
[Falling Waveform]
V_fixture = 0V
V_fixture_min = 0V
V_fixture_max = 0V
R_fixture = 50Ohm
|   Time   V(typ)   V(min)   V(max)
0s        915.4mV    769.5mV    1.065V
373.2ps   925.7mV    770.5mV    1.089V
569.3ps   929.1mV    772.3mV    1.031V
882.3ps   859.5mV    772.9mV    615.9mV
1.208ns   520.6mV    766.3mV    308.7mV
1.515ns   182.2mV    701.6mV    180.6mV
1.726ns   75.81mV    556.4mV    135.5mV
2.053ns   15.57mV    204.8mV    101.3mV
2.601ns   2.552mV    24.92mV    72.23mV
5.879ns   83.66uV    64.9uV     6.108mV
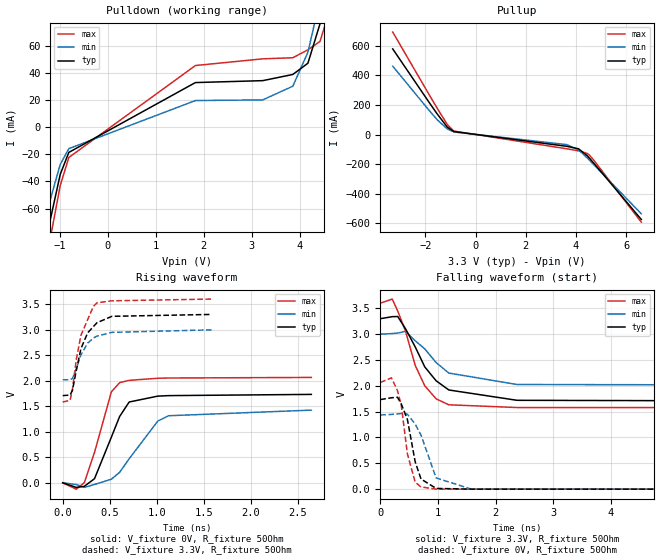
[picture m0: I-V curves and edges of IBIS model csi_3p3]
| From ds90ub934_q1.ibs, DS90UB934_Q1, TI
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|   csi_3p3 Model
[Model]   csi_3p3
Model_type   Output
Polarity   Non-Inverting
Vmeas = 1.65
Vref = 0
Cref = 2pF
Rref = 70
|   typ   min   max
|   (nom PVT)   (fast PVT)   (slow PVT)
C_comp   3.130e-13   3.062e-13   3.389e-13
| Where nom  PVT is Nominal Process, 3.3V, 27C
|   Fast PVT is Strong Process,  3.6V, -40C
|   Slow PVT is Weak Process,   3V, 125C
[Voltage Range]   3.3   3   3.6
|Junction Temperature
[Temperature Range]   27   125   -40
[Pullup Reference]   3.3   3   3.6
[Pulldown Reference]   0   0   0
[Power Clamp Reference]   3.3   3   3.6
[GND Clamp Reference]   0   0   0
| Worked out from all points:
|   slope of the pulldown table from 0 to 0.495 V, typ, clamps not added: 47.3 ohm
|   slope of the pullup table from 0 to 0.495 V, typ, clamps not added: 44.8 ohm
|   falling waveform, V_fixture 3.3V, R_fixture 50Ohm: 20-80 % time 530ps typ, 567ps min, 383ps max; typ from 3.3 V to 1.71 V
|   rising waveform, V_fixture 0V, R_fixture 50Ohm: 20-80 % time 222ps typ, 338ps min, 181ps max; typ from 0 V to 1.73 V
|   rising waveform, V_fixture 3.3V, R_fixture 50Ohm: 20-80 % time 155ps typ, 161ps min, 151ps max; typ from 1.71 V to 3.3 V
|   falling waveform, V_fixture 0V, R_fixture 50Ohm: 20-80 % time 189ps typ, 265ps min, 156ps max; typ from 1.73 V to 0 V
[Pulldown]
|   Voltage   I(typ)   I(min)   I(max)
-3.3V     -453.3mA   -387.2mA   -510.4mA
-1.597V   -137.7mA   -111.7mA   -160.6mA
-1.28V    -81.12mA   -63.36mA   -97.09mA
-992.4mV  -34.71mA   -27.42mA   -42.91mA
-813mV    -18.58mA   -15.83mA   -22.32mA
1.825V    32.8mA     19.56mA    45.34mA
3.228V    34.21mA    20.05mA    50.27mA
3.855V    38.76mA    30.11mA    51.06mA
4.17V     47.04mA    55.14mA    56.91mA
4.422V    76.08mA    93.71mA    63.08mA
4.623V    118.2mA    131.5mA    86.1mA
6.6V      605.8mA    537.5mA    647.2mA
[Pullup]
|   Voltage   I(typ)   I(min)   I(max)
-3.3V     579.7mA    463mA      693.3mA
-1.885V   226.8mA    171.2mA    280.8mA
-1.671V   174.5mA    128.7mA    219.2mA
-1.515V   137mA      98.66mA    174.7mA
-1.119V   49.6mA     37.87mA    66.64mA
-861.3mV  20.85mA    18.23mA    24.18mA
3.634V    -78.75mA   -67.28mA   -95.65mA
4.104V    -95.78mA   -103.2mA   -109.5mA
4.447V    -142.8mA   -157.8mA   -126.7mA
4.534V    -159.1mA   -172.7mA   -138.5mA
4.689V    -189mA     -199.5mA   -168.5mA
6.6V      -573.3mA   -535.2mA   -591.6mA
[Ramp]
R_load = 50
|   typ   min   max
dV/dt_r   1.0399/2.22447e-10   0.859982/3.40916e-10   1.23815/1.80911e-10
dV/dt_f   0.955891/5.32059e-10   0.589476/5.67535e-10   1.21166/3.82211e-10
[Falling Waveform]
V_fixture = 3.3V
V_fixture_min = 3V
V_fixture_max = 3.6V
R_fixture = 50Ohm
|   Time   V(typ)   V(min)   V(max)
0s        3.3V       3V         3.6V
207.4ps   3.339V     3.012V     3.68V
303ps     3.342V     3.022V     3.448V
438.3ps   3.105V     3.055V     3.056V
605.6ps   2.755V     2.873V     2.397V
771.6ps   2.367V     2.716V     2.002V
968.4ps   2.098V     2.451V     1.749V
1.189ns   1.92V      2.247V     1.633V
2.372ns   1.72V      2.026V     1.58V
6.514ns   1.709V     2.018V     1.579V
[Rising Waveform]
V_fixture = 0V
V_fixture_min = 0V
V_fixture_max = 0V
R_fixture = 50Ohm
|   Time   V(typ)   V(min)   V(max)
0s        10.78uV    36.95uV    6.21uV
143.9ps   -90.31mV   -34.19mV   -125mV
229.5ps   -70mV      -90.14mV   1.211mV
338.3ps   80.34mV    -33.4mV    594.8mV
517.7ps   894.7mV    69.94mV    1.782V
605.6ps   1.299V     205.2mV    1.961V
706.7ps   1.582V     469.5mV    2.006V
1.011ns   1.697V     1.208V     2.047V
1.126ns   1.707V     1.313V     2.052V
2.644ns   1.731V     1.423V     2.063V
[Rising Waveform]
V_fixture = 3.3V
V_fixture_min = 3V
V_fixture_max = 3.6V
R_fixture = 50Ohm
|   Time   V(typ)   V(min)   V(max)
0s        1.707V     2.018V     1.581V
78.84ps   1.718V     2.017V     1.616V
103.7ps   1.812V     2.044V     1.834V
143.9ps   2.194V     2.225V     2.409V
193.7ps   2.626V     2.506V     2.886V
265.2ps   2.936V     2.734V     3.194V
326.3ps   3.059V     2.834V     3.454V
364.2ps   3.134V     2.873V     3.525V
523.2ps   3.26V      2.946V     3.564V
1.582ns   3.297V     2.995V     3.598V
[Falling Waveform]
V_fixture = 0V
V_fixture_min = 0V
V_fixture_max = 0V
R_fixture = 50Ohm
|   Time   V(typ)   V(min)   V(max)
0s        1.734V     1.436V     2.064V
193.7ps   1.769V     1.447V     2.155V
297.9ps   1.779V     1.456V     1.908V
364.2ps   1.65V      1.465V     1.624V
470.6ps   1.349V     1.451V     682.6mV
605.6ps   528.5mV    1.26V      134.9mV
706.7ps   195.7mV    1.046V     42.16mV
968.4ps   14.4mV     216.9mV    528.4uV
1.582ns   202.5uV    483.7uV    200uV
100ns     380.2uV    226.3uV    -260uV
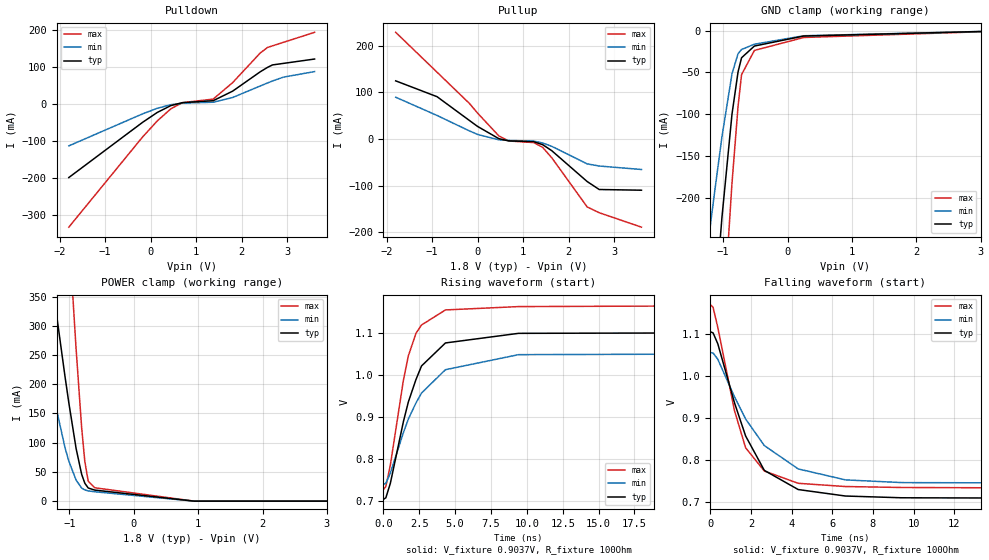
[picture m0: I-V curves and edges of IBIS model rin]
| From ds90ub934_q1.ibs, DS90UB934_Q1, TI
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|   rin Model
[Model]   rin
Model_type   I/O
Polarity   Inverting
Enable   Active-Low
Vinl = 0.63
Vinh = 1.17
Vmeas = 0.9
Vref = 0.9037V
Cref = 2pF
Rref = 100
|   typ   min   max
|   (nom PVT)   (fast PVT)   (slow PVT)
C_comp   1.332e-12   1.050e-12   1.635e-12
| Where nom  PVT is Nominal Process, 1.8V, 27C
|   Fast PVT is Strong Process,  1.89V, -40C
|   Slow PVT is Weak Process,   1.71V, 125C
[Voltage Range]   1.8   1.71   1.89
|Junction Temperature
[Temperature Range]   27   125   -40
[Pullup Reference]   1.8   1.71   1.89
[Pulldown Reference]   0   0   0
[Power Clamp Reference]   1.8   1.71   1.89
[GND Clamp Reference]   0   0   0
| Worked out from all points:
|   slope of the pulldown table from 0 to 0.27 V, typ, clamps not added: 13.8 ohm
|   slope of the pullup table from 0 to 0.27 V, typ, clamps not added: 15.9 ohm
|   falling waveform, V_fixture 0.9037V, R_fixture 100Ohm: 20-80 % time 1.83ns typ, 2.51ns min, 1.38ns max; typ from 1.11 V to 0.705 V
|   rising waveform, V_fixture 0.9037V, R_fixture 100Ohm: 20-80 % time 1.93ns typ, 2.59ns min, 1.44ns max; typ from 0.703 V to 1.1 V
[Pulldown]
|   Voltage   I(typ)   I(min)   I(max)
-1.8V     -199.3mA   -113.3mA   -334mA
-180mV    -49.45mA   -26.42mA   -89.3mA
142.6mV   -22.62mA   -11.24mA   -45.67mA
441.8mV   -3.94mA    -1.502mA   -12.62mA
696.6mV   3.963mA    2.702mA    4.07mA
1.372V    9.37mA     5.203mA    13.68mA
1.799V    35.23mA    17.96mA    58.4mA
2.405V    87.76mA    49.29mA    138.8mA
2.566V    99.83mA    57.52mA    153.9mA
2.675V    106.5mA    62.88mA    158.3mA
2.914V    110.6mA    73.31mA    167.8mA
3.6V      122.5mA    88.41mA    195mA
[GND Clamp]
|   Voltage   I(typ)   I(min)   I(max)
-1.8V     -1.074A    -627.4mA   -1.965A
-1.465V   -684.5mA   -400.1mA   -1.234A
-1.318V   -524.8mA   -306.5mA   -923.4mA
-1.202V   -402.9mA   -234.2mA   -686mA
-1.129V   -329.3mA   -190.5mA   -547.2mA
-1.018V   -222.2mA   -126.3mA   -367.7mA
-862.6mV  -99.71mA   -51.58mA   -182mA
-768.6mV  -49.41mA   -27.64mA   -90.59mA
-714.1mV  -32.48mA   -22.62mA   -52.63mA
-514.8mV  -18.51mA   -16.31mA   -23.73mA
252mV     -6.584mA   -6.245mA   -8.3mA
3.6V      0A         0A         0A
[Pullup]
|   Voltage   I(typ)   I(min)   I(max)
-1.8V     124.6mA    89.56mA    228.5mA
-890.9mV  90.68mA    50.49mA    143.1mA
-180mV    39.78mA    17.44mA    76.22mA
630uV     26.94mA    9.845mA    55.41mA
467.5mV   772.1uA    -1.551mA   6.678mA
682.9mV   -3.898mA   -3.013mA   -4.095mA
1.233V    -5.663mA   -4.33mA    -7.521mA
1.429V    -12mA      -8.465mA   -17.75mA
1.629V    -24.88mA   -15.58mA   -40mA
2.407V    -90.93mA   -53.13mA   -145.3mA
2.672V    -108mA     -57.72mA   -157.7mA
3.6V      -109.5mA   -65.17mA   -188.6mA
[POWER Clamp]
|   Voltage   I(typ)   I(min)   I(max)
-1.8V     815.9mA    473.9mA    1.986A
-1.47V    538.6mA    292.5mA    1.34A
-1.415V   492.8mA    263mA      1.233A
-1.069V   213.8mA    91.81mA    572.2mA
-1.01V    169mA      68.84mA    462.7mA
-896.4mV  90.37mA    36.14mA    261.2mA
-810mV    46.09mA    22.37mA    126.1mA
-760.5mV  30.62mA    19.13mA    67.95mA
-707.6mV  22.48mA    17.59mA    34.06mA
-607.4mV  18.92mA    16.05mA    22.91mA
936.7mV   0A         0A         10.32uA
3.6V      0A         0A         0A
[Ramp]
R_load = 100
|   typ   min   max
dV/dt_r   0.115936/1.07574e-09   0.0813861/1.40573e-09  0.141793/1.00654e-09
dV/dt_f   0.241583/1.85488e-09   0.190076/2.54897e-09   0.267148/1.40058e-09
[Falling Waveform]
V_fixture = 0.9037V
V_fixture_min = 0.897V
V_fixture_max = 0.9482V
R_fixture = 100Ohm
|   Time   V(typ)   V(min)   V(max)
0s        1.106V     1.056V     1.171V
139ps     1.103V     1.055V     1.164V
370.8ps   1.077V     1.04V      1.116V
1.191ns   936mV      950.3mV    917.3mV
1.738ns   856.7mV    897.3mV    828.5mV
2.659ns   774.4mV    833.7mV    772.9mV
4.325ns   728.6mV    777.9mV    743.5mV
6.65ns    713.1mV    751.7mV    735.8mV
9.422ns   708.9mV    745.2mV    733.5mV
41.07ns   705.2mV    741.2mV    728.3mV
[Rising Waveform]
V_fixture = 0.9037V
V_fixture_min = 0.897V
V_fixture_max = 0.9482V
R_fixture = 100Ohm
|   Time   V(typ)   V(min)   V(max)
0s        702.8mV    738.7mV    726mV
170.1ps   706.5mV    741mV      733.4mV
484.3ps   741.1mV    765.7mV    784.7mV
1.392ns   888.4mV    862.3mV    987.4mV
1.738ns   935.7mV    894.9mV    1.046V
2.27ns    989.5mV    933.4mV    1.1V
2.659ns   1.022V     957.3mV    1.12V
4.325ns   1.077V     1.013V     1.156V
9.422ns   1.1V       1.049V     1.164V
49.07ns   1.103V     1.053V     1.169V
